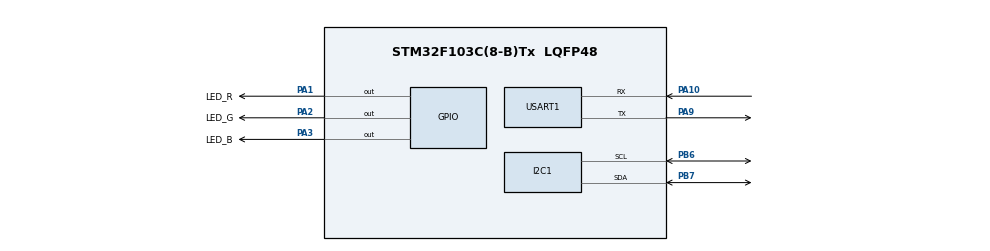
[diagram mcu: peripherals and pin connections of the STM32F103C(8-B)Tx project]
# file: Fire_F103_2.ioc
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FREERTOS.Tasks01=defaultTask,0,128,StartDefaultTask,Default,NULL,Dynamic,NULL,NULL;ledTask,0,128,StartLEDTask,Default,NULL,Dynamic,NULL,NULL;uartTask,-2,256,StartUartTAsk,Default,NULL,Dynamic,NULL,NULL
Mcu.Family=STM32F1
Mcu.Name=STM32F103C(8-B)Tx
Mcu.Package=LQFP48
NVIC.PriorityGroup=NVIC_PRIORITYGROUP_4
PA1.GPIO_Label=LED_R
PA1.PinState=GPIO_PIN_SET
PA1.Signal=GPIO_Output
PA10.Mode=Asynchronous
PA10.Signal=USART1_RX
PA13.Mode=Serial_Wire
PA13.Signal=SYS_JTMS-SWDIO
PA14.Mode=Serial_Wire
PA14.Signal=SYS_JTCK-SWCLK
PA2.GPIO_Label=LED_G
PA2.PinState=GPIO_PIN_SET
PA2.Signal=GPIO_Output
PA3.GPIO_Label=LED_B
PA3.PinState=GPIO_PIN_SET
PA3.Signal=GPIO_Output
PA9.Mode=Asynchronous
PA9.Signal=USART1_TX
PB6.Mode=I2C
PB6.Signal=I2C1_SCL
PB7.Mode=I2C
PB7.Signal=I2C1_SDA
PC14-OSC32_IN.Mode=LSE-External-Oscillator
PC14-OSC32_IN.Signal=RCC_OSC32_IN
PC15-OSC32_OUT.Mode=LSE-External-Oscillator
PC15-OSC32_OUT.Signal=RCC_OSC32_OUT
PD0-OSC_IN.Mode=HSE-External-Oscillator
PD0-OSC_IN.Signal=RCC_OSC_IN
PD1-OSC_OUT.Mode=HSE-External-Oscillator
PD1-OSC_OUT.Signal=RCC_OSC_OUT
ProjectManager.HeapSize=0x200
ProjectManager.StackSize=0x400
ProjectManager.TargetToolchain=MDK-ARM V5.32
RCC.AHBFreq_Value=72000000
RCC.APB1CLKDivider=RCC_HCLK_DIV2
RCC.APB1Freq_Value=36000000
RCC.APB1TimFreq_Value=72000000
RCC.APB2Freq_Value=72000000
RCC.APB2TimFreq_Value=72000000
RCC.HCLKFreq_Value=72000000
RCC.PLLMUL=RCC_PLL_MUL9
RCC.PLLSourceVirtual=RCC_PLLSOURCE_HSE
RCC.SYSCLKFreq_VALUE=72000000
RCC.SYSCLKSource=RCC_SYSCLKSOURCE_PLLCLK
RCC.USBFreq_Value=72000000
USART1.VirtualMode=VM_ASYNC
VP_FREERTOS_VS_CMSIS_V1.Mode=CMSIS_V1
board=custom

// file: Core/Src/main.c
/* USER CODE BEGIN Header */
/**
  ******************************************************************************
  * @file           : main.c
  * @brief          : Main program body
  ******************************************************************************
  * @attention
  *
  * Copyright (c) 2026 STMicroelectronics.
  * All rights reserved.
  *
  * This software is licensed under terms that can be found in the LICENSE file
  * in the root directory of this software component.
  * If no LICENSE file comes with this software, it is provided AS-IS.
  *
  ******************************************************************************
  */
/* USER CODE END Header */
#include "main.h"
#include "cmsis_os.h"
#include "i2c.h"
#include "usart.h"
#include "gpio.h"

/* USER CODE BEGIN Includes */
#include <string.h>
#include <stdio.h>
#include "bsp_i2c_oled.h"
#include "bsp_fonts.h"
/* USER CODE END Includes */

/* USER CODE BEGIN PV */
volatile uint8_t g_oled_ready = 0U;

/* USER CODE END PV */

void SystemClock_Config(void);
void MX_FREERTOS_Init(void);
/* USER CODE BEGIN PFP */
static void Debug_SendText(const char *text);

/* USER CODE END PFP */

/* USER CODE BEGIN 0 */
static void Debug_SendText(const char *text)
{
  if (text == NULL)
  {
    return;
  }

  HAL_UART_Transmit(&huart1, (uint8_t *)text, (uint16_t)strlen(text), 100);
}

/* USER CODE END 0 */

int main(void)
{

  /* MCU Configuration--------------------------------------------------------*/

  /* Reset of all peripherals, Initializes the Flash interface and the Systick. */
  HAL_Init();

  /* Configure the system clock */
  SystemClock_Config();

  /* Initialize all configured peripherals */
  MX_GPIO_Init();
  MX_USART1_UART_Init();
  MX_I2C1_Init();
  /* USER CODE BEGIN 2 */
  Debug_SendText("BOOT\r\n");
  if (OLED_Init() == SUCCESS)
  {
    g_oled_ready = 1U;
    OLED_ShowString_F8X16(0,0, (uint8_t*)"STM32");
    OLED_ShowString_F8X16(1,0, (uint8_t*)"FreeRTOS");
    OLED_ShowString_F8X16(2,0, (uint8_t*)"LED OK");
    Debug_SendText("OLED READY\r\n");
  }
  else
  {
    Debug_SendText("OLED FAIL\r\n");
  }
  /* USER CODE END 2 */
  /* Call init function for freertos objects (in cmsis_os2.c) */
  MX_FREERTOS_Init();
  Debug_SendText("RTOS INIT\r\n");
  /* Start scheduler */
  osKernelStart();
  Debug_SendText("RTOS START FAIL\r\n");

  /* We should never get here as control is now taken by the scheduler */

  /* Infinite loop */
  while (1)
  {

    /* USER CODE BEGIN 3 */
    HAL_GPIO_TogglePin(GPIOA, LED_R_Pin);
    if (g_oled_ready == 0U)
    {
      g_oled_ready = (OLED_Init() == SUCCESS) ? 1U : 0U;
    }

    if (g_oled_ready != 0U)
    {
      OLED_CLS();
      OLED_ShowString_F8X16(0,0, (uint8_t*)"STM32");
      OLED_ShowString_F8X16(1,0, (uint8_t*)"FreeRTOS");
      OLED_ShowString_F8X16(2,0, (uint8_t*)"LED OK");
    }

    Debug_SendText("FALLBACK LOOP\r\n");
    HAL_Delay(1000);
  }
  /* USER CODE END 3 */
}

void SystemClock_Config(void)
{
  RCC_OscInitTypeDef RCC_OscInitStruct = {0};
  RCC_ClkInitTypeDef RCC_ClkInitStruct = {0};

  /** Initializes the RCC Oscillators according to the specified parameters
  * in the RCC_OscInitTypeDef structure.
  */
  RCC_OscInitStruct.OscillatorType = RCC_OSCILLATORTYPE_HSE;
  RCC_OscInitStruct.HSEState = RCC_HSE_ON;
  RCC_OscInitStruct.HSEPredivValue = RCC_HSE_PREDIV_DIV1;
  RCC_OscInitStruct.HSIState = RCC_HSI_ON;
  RCC_OscInitStruct.PLL.PLLState = RCC_PLL_ON;
  RCC_OscInitStruct.PLL.PLLSource = RCC_PLLSOURCE_HSE;
  RCC_OscInitStruct.PLL.PLLMUL = RCC_PLL_MUL9;
  if (HAL_RCC_OscConfig(&RCC_OscInitStruct) != HAL_OK)
  {
    RCC_OscInitStruct.OscillatorType = RCC_OSCILLATORTYPE_HSI;
    RCC_OscInitStruct.HSEState = RCC_HSE_OFF;
    RCC_OscInitStruct.HSIState = RCC_HSI_ON;
    RCC_OscInitStruct.PLL.PLLState = RCC_PLL_OFF;
    if (HAL_RCC_OscConfig(&RCC_OscInitStruct) != HAL_OK)
    {
      Error_Handler();
    }

    RCC_ClkInitStruct.ClockType = RCC_CLOCKTYPE_HCLK|RCC_CLOCKTYPE_SYSCLK
                                |RCC_CLOCKTYPE_PCLK1|RCC_CLOCKTYPE_PCLK2;
    RCC_ClkInitStruct.SYSCLKSource = RCC_SYSCLKSOURCE_HSI;
    RCC_ClkInitStruct.AHBCLKDivider = RCC_SYSCLK_DIV1;
    RCC_ClkInitStruct.APB1CLKDivider = RCC_HCLK_DIV1;
    RCC_ClkInitStruct.APB2CLKDivider = RCC_HCLK_DIV1;
    if (HAL_RCC_ClockConfig(&RCC_ClkInitStruct, FLASH_LATENCY_0) != HAL_OK)
    {
      Error_Handler();
    }
    return;
  }

  /** Initializes the CPU, AHB and APB buses clocks
  */
  RCC_ClkInitStruct.ClockType = RCC_CLOCKTYPE_HCLK|RCC_CLOCKTYPE_SYSCLK
                              |RCC_CLOCKTYPE_PCLK1|RCC_CLOCKTYPE_PCLK2;
  RCC_ClkInitStruct.SYSCLKSource = RCC_SYSCLKSOURCE_PLLCLK;
  RCC_ClkInitStruct.AHBCLKDivider = RCC_SYSCLK_DIV1;
  RCC_ClkInitStruct.APB1CLKDivider = RCC_HCLK_DIV2;
  RCC_ClkInitStruct.APB2CLKDivider = RCC_HCLK_DIV1;

  if (HAL_RCC_ClockConfig(&RCC_ClkInitStruct, FLASH_LATENCY_2) != HAL_OK)
  {
    Error_Handler();
  }
}

/* USER CODE BEGIN 4 */
int fputc(int ch,FILE*f)
{
	(void)f;
	HAL_UART_Transmit(&huart1,(uint8_t *)&ch, 1 , HAL_MAX_DELAY);
	return ch;

}

/* USER CODE END 4 */

void Error_Handler(void)
{
  /* USER CODE BEGIN Error_Handler_Debug */
  /* User can add his own implementation to report the HAL error return state */
  if (huart1.Instance == USART1)
  {
    Debug_SendText("ERROR HANDLER\r\n");
  }
  __disable_irq();
  while (1)
  {
  }
  /* USER CODE END Error_Handler_Debug */
}

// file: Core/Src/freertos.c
/* USER CODE BEGIN Header */
/**
  ******************************************************************************
  * File Name          : freertos.c
  * Description        : Code for freertos applications
  ******************************************************************************
  * @attention
  *
  * Copyright (c) 2026 STMicroelectronics.
  * All rights reserved.
  *
  * This software is licensed under terms that can be found in the LICENSE file
  * in the root directory of this software component.
  * If no LICENSE file comes with this software, it is provided AS-IS.
  *
  ******************************************************************************
  */
/* USER CODE END Header */

#include "FreeRTOS.h"
#include "task.h"
#include "main.h"
#include "cmsis_os.h"

/* USER CODE BEGIN Includes */
#include "gpio.h"
#include "usart.h"
#include "i2c.h"
#include "bsp_i2c_oled.h"
#include <string.h>

/* USER CODE END Includes */

/* USER CODE BEGIN Variables */
volatile uint32_t led_count=0;
volatile uint32_t uart_count=0;

/* USER CODE END Variables */
osThreadId defaultTaskHandle;
osThreadId ledTaskHandle;
osThreadId uartTaskHandle;

/* USER CODE BEGIN FunctionPrototypes */
static void DebugTaskSend(const char *text);

/* USER CODE END FunctionPrototypes */

void StartDefaultTask(void const * argument);
void StartLEDTask(void const * argument);
void StartUartTAsk(void const * argument);

void MX_FREERTOS_Init(void); /* (MISRA C 2004 rule 8.1) */

extern volatile uint8_t g_oled_ready;

/* GetIdleTaskMemory prototype (linked to static allocation support) */
void vApplicationGetIdleTaskMemory( StaticTask_t **ppxIdleTaskTCBBuffer, StackType_t **ppxIdleTaskStackBuffer, uint32_t *pulIdleTaskStackSize );

/* USER CODE BEGIN GET_IDLE_TASK_MEMORY */
static StaticTask_t xIdleTaskTCBBuffer;
static StackType_t xIdleStack[configMINIMAL_STACK_SIZE];

void vApplicationGetIdleTaskMemory( StaticTask_t **ppxIdleTaskTCBBuffer, StackType_t **ppxIdleTaskStackBuffer, uint32_t *pulIdleTaskStackSize )
{
  *ppxIdleTaskTCBBuffer = &xIdleTaskTCBBuffer;
  *ppxIdleTaskStackBuffer = &xIdleStack[0];
  *pulIdleTaskStackSize = configMINIMAL_STACK_SIZE;
  /* place for user code */
}

static void DebugTaskSend(const char *text)
{
  if (text == NULL)
  {
    return;
  }

  HAL_UART_Transmit(&huart1, (uint8_t *)text, (uint16_t)strlen(text), 100);
}
/* USER CODE END GET_IDLE_TASK_MEMORY */

void MX_FREERTOS_Init(void) {

  /* Create the thread(s) */
  /* definition and creation of defaultTask */
  osThreadDef(defaultTask, StartDefaultTask, osPriorityNormal, 0, 128);
	defaultTaskHandle = osThreadCreate(osThread(defaultTask), NULL);
  if(defaultTaskHandle == NULL)
  {
    DebugTaskSend("defaultTask create fail\r\n");
    Error_Handler();
  }

  /* definition and creation of ledTask */
  osThreadDef(ledTask, StartLEDTask, osPriorityNormal, 0, 512);
  ledTaskHandle = osThreadCreate(osThread(ledTask), NULL);
	if(ledTaskHandle==NULL)
	{
    DebugTaskSend("ledTask create fail\r\n");
		Error_Handler();
	}

  /* definition and creation of uartTask */
  osThreadDef(uartTask, StartUartTAsk, osPriorityLow, 0, 256);
  uartTaskHandle = osThreadCreate(osThread(uartTask), NULL);
		if(uartTaskHandle==NULL)
	{
    DebugTaskSend("uartTask create fail\r\n");
		Error_Handler();
	}

}

void StartDefaultTask(void const * argument)
{
  for(;;)
  {
    osDelay(1);
  }
}

void StartLEDTask(void const * argument)
{
  /* USER CODE BEGIN StartLEDTask */
  /* Infinite loop */
  for(;;)
  {
        if (g_oled_ready == 0U)
        {
          g_oled_ready = (OLED_Init() == SUCCESS) ? 1U : 0U;
          osDelay(200);
          continue;
        }

				OLED_CLS();
        OLED_ShowString_F8X16(0,0, (uint8_t*)"STM32");
        OLED_ShowString_F8X16(1,0, (uint8_t*)"FreeRTOS");
        OLED_ShowString_F8X16(2,0, (uint8_t*)"LED OK");
				osDelay(1000);
  }
  /* USER CODE END StartLEDTask */
}

void StartUartTAsk(void const * argument)
{
  /* USER CODE BEGIN StartUartTAsk */
	 const char msg[] = "USART1 send ok\r\n";
  /* Infinite loop */
  for(;;)
  {
		HAL_GPIO_TogglePin(GPIOA,LED_R_Pin);
	  HAL_UART_Transmit(&huart1, (uint8_t *)msg, (uint16_t)(sizeof(msg) - 1), HAL_MAX_DELAY);
    osDelay(1000);
  }
  /* USER CODE END StartUartTAsk */
}

/* USER CODE BEGIN Application */
void vApplicationMallocFailedHook(void)
{
  DebugTaskSend("RTOS malloc failed\r\n");
  __disable_irq();
  while (1)
  {
  }
}

void vApplicationStackOverflowHook(TaskHandle_t xTask, char *pcTaskName)
{
  (void)xTask;
  DebugTaskSend("RTOS stack overflow: ");
  DebugTaskSend(pcTaskName);
  DebugTaskSend("\r\n");
  __disable_irq();
  while (1)
  {
  }
}

/* USER CODE END Application */
